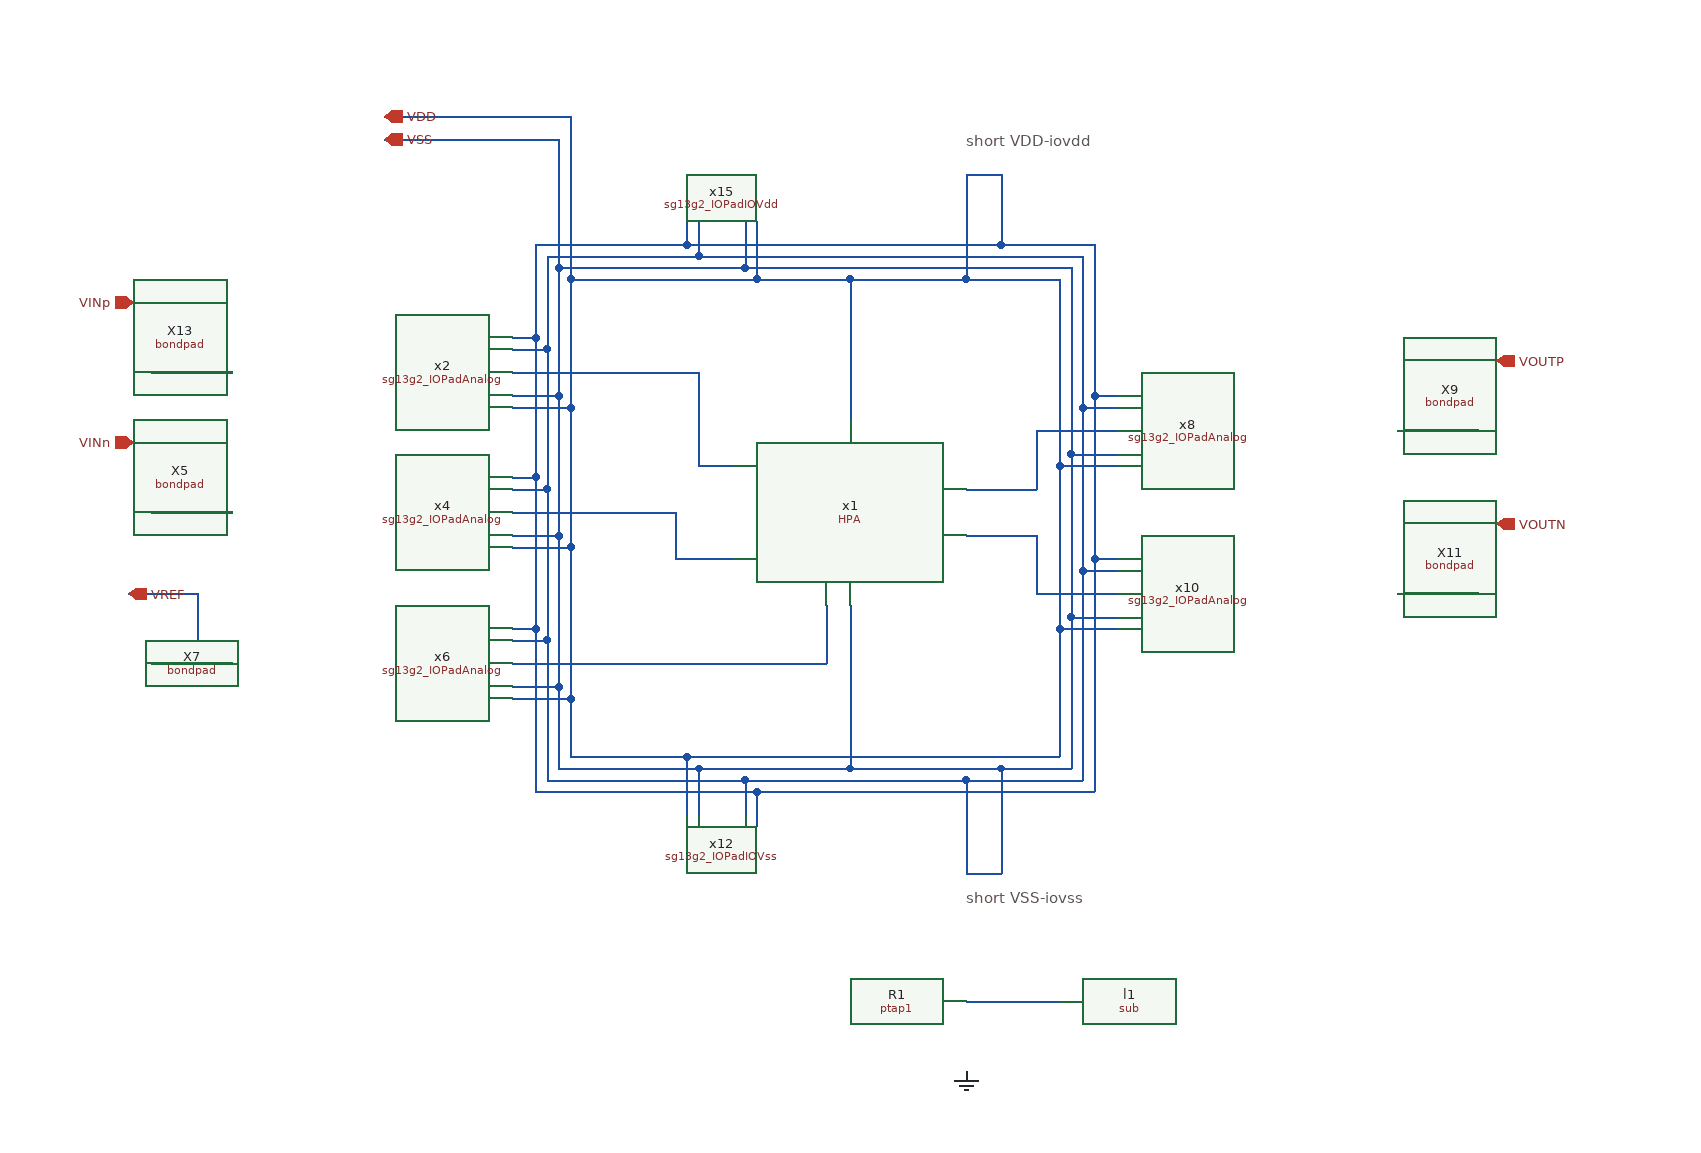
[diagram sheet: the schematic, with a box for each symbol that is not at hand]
v {xschem version=3.4.4 file_version=1.2
}
G {}
K {}
V {}
S {}
E {}
T {short VDD-iovdd} 100 -330 0 0 0.4 0.4 {}
T {short VSS-iovss} 100 320 0 0 0.4 0.4 {}
N -560 0 -530 0 {
lab=VINn}
N -620 -60 -560 -60 {
lab=VINn}
N -560 -60 -560 0 {
lab=VINn}
N -600 0 -560 0 {
lab=VINn}
N -560 130 -530 130 {
lab=VREF}
N -620 70 -560 70 {
lab=VREF}
N -560 70 -560 130 {
lab=VREF}
N -600 130 -560 130 {
lab=VREF}
N -560 -120 -530 -120 {
lab=VINp}
N -620 -180 -560 -180 {
lab=VINp}
N -560 -180 -560 -120 {
lab=VINp}
N -600 -120 -560 -120 {
lab=VINp}
N 470 -70 500 -70 {
lab=VOUTP}
N 500 -130 560 -130 {
lab=VOUTP}
N 500 -130 500 -70 {
lab=VOUTP}
N 500 -70 540 -70 {
lab=VOUTP}
N 470 70 500 70 {
lab=VOUTN}
N 500 10 560 10 {
lab=VOUTN}
N 500 10 500 70 {
lab=VOUTN}
N 500 70 540 70 {
lab=VOUTN}
N -80 -250 -80 -200 {
lab=VDD}
N -240 160 -240 210 {
lab=VDD}
N -90 -250 -90 -210 {
lab=VSS}
N -250 150 -250 220 {
lab=VSS}
N -250 220 -130 220 {
lab=VSS}
N -130 220 -130 260 {
lab=VSS}
N -140 210 -140 260 {
lab=VDD}
N -240 210 -140 210 {
lab=VDD}
N 130 220 190 220 {
lab=VSS}
N -130 -250 -130 -220 {
lab=VSS}
N -260 110 -260 230 {
lab=VSS}
N 100 230 200 230 {
lab=VSS}
N -140 -250 -140 -230 {
lab=VDD}
N -270 -230 -140 -230 {
lab=VDD}
N -80 240 210 240 {
lab=VDD}
N -270 100 -270 240 {
lab=VDD}
N -290 -150 -270 -150 {
lab=VDD}
N -270 -230 -270 -150 {
lab=VDD}
N -290 -140 -260 -140 {
lab=VSS}
N -260 -220 -260 -140 {
lab=VSS}
N -290 -30 -270 -30 {
lab=VDD}
N -270 -150 -270 -30 {
lab=VDD}
N -290 -20 -260 -20 {
lab=VSS}
N -260 -140 -260 -20 {
lab=VSS}
N -290 100 -270 100 {
lab=VDD}
N -270 -30 -270 100 {
lab=VDD}
N -290 110 -260 110 {
lab=VSS}
N -260 -20 -260 110 {
lab=VSS}
N -290 160 -240 160 {
lab=VDD}
N -240 30 -240 160 {
lab=VDD}
N -290 150 -250 150 {
lab=VSS}
N -250 20 -250 150 {
lab=VSS}
N -290 -90 -240 -90 {
lab=VDD}
N -290 -100 -250 -100 {
lab=VSS}
N -250 -210 -250 -100 {
lab=VSS}
N 180 100 180 210 {
lab=VDD}
N 100 -200 180 -200 {
lab=VDD}
N 190 90 190 220 {
lab=VSS}
N -90 -210 190 -210 {
lab=VSS}
N 200 50 200 230 {
lab=VSS}
N -130 -220 200 -220 {
lab=VSS}
N -260 -220 -130 -220 {
lab=VSS}
N 210 40 210 240 {
lab=VDD}
N 130 -230 210 -230 {
lab=VDD}
N 210 -100 230 -100 {
lab=VDD}
N 210 -230 210 -100 {
lab=VDD}
N 200 -90 230 -90 {
lab=VSS}
N 200 -220 200 -90 {
lab=VSS}
N 190 -50 230 -50 {
lab=VSS}
N 190 -210 190 -50 {
lab=VSS}
N 180 -40 230 -40 {
lab=VDD}
N 180 -200 180 -40 {
lab=VDD}
N 210 40 230 40 {
lab=VDD}
N 210 -100 210 40 {
lab=VDD}
N 200 50 230 50 {
lab=VSS}
N 200 -90 200 50 {
lab=VSS}
N 190 90 230 90 {
lab=VSS}
N 190 -50 190 90 {
lab=VSS}
N 180 100 230 100 {
lab=VDD}
N 180 -40 180 100 {
lab=VDD}
N -140 210 180 210 {
lab=VDD}
N -130 220 0 220 {
lab=VSS}
N -240 -200 -80 -200 {
lab=VDD}
N -250 -210 -90 -210 {
lab=VSS}
N -250 -320 -250 -210 {
lab=VSS}
N -240 -200 -240 -90 {
lab=VDD}
N -400 -320 -250 -320 {
lab=VSS}
N -240 -340 -240 -200 {
lab=VDD}
N -400 -340 -240 -340 {
lab=VDD}
N 0 -200 0 -80 {
lab=VDD}
N -80 -200 0 -200 {
lab=VDD}
N 0 80 0 220 {
lab=VSS}
N 100 -20 160 -20 {
lab=#net1}
N 160 -70 160 -20 {
lab=#net1}
N 160 -70 230 -70 {
lab=#net1}
N 100 20 160 20 {
lab=#net2}
N 160 20 160 70 {
lab=#net2}
N 160 70 230 70 {
lab=#net2}
N 100 -290 100 -200 {
lab=VDD}
N 0 -200 100 -200 {
lab=VDD}
N 100 -290 130 -290 {
lab=VDD}
N 130 -290 130 -230 {
lab=VDD}
N -140 -230 130 -230 {
lab=VDD}
N 130 220 130 310 {
lab=VSS}
N 100 310 130 310 {
lab=VSS}
N 0 220 130 220 {
lab=VSS}
N 100 230 100 310 {
lab=VSS}
N -90 230 100 230 {
lab=VSS}
N -20 80 -20 130 {
lab=#net3}
N -290 130 -20 130 {
lab=#net3}
N -290 -120 -130 -120 {
lab=#net4}
N -130 -120 -130 -40 {
lab=#net4}
N -130 -40 -100 -40 {
lab=#net4}
N -290 0 -150 -0 {
lab=#net5}
N -150 40 -100 40 {
lab=#net5}
N -150 -0 -150 40 {
lab=#net5}
N -290 20 -250 20 {
lab=VSS}
N -250 -100 -250 20 {
lab=VSS}
N -290 30 -240 30 {
lab=VDD}
N -240 -90 -240 30 {
lab=VDD}
N -80 240 -80 270 {
lab=VDD}
N -270 240 -80 240 {
lab=VDD}
N -90 230 -90 260 {
lab=VSS}
N -260 230 -90 230 {
lab=VSS}
N 100 420 180 420 {}
C {HPA.sym} -20 0 0 0 {name=x1}
C {sg13g2_IOPadIOVdd.sym} -110 -370 3 0 {name=x15}
C {sg13g2_IOPadIOVss.sym} -110 380 1 0 {name=x12}
C {sg13g2_pr/bondpad.sym} -640 0 3 0 {name=X5
model=bondpad
spiceprefix=X
size=80u
shape=0
padtype=0
}
C {sg13g2_pr/bondpad.sym} -640 130 3 0 {name=X7
model=bondpad
spiceprefix=X
size=80u
shape=0
padtype=0
}
C {sg13g2_pr/bondpad.sym} -640 -120 3 0 {name=X13
model=bondpad
spiceprefix=X
size=80u
shape=0
padtype=0
}
C {IOCells/sg13g2_IOPadAnalog.sym} -410 -120 0 1 {name=x2}
C {IOCells/sg13g2_IOPadAnalog.sym} -410 0 0 1 {name=x4}
C {IOCells/sg13g2_IOPadAnalog.sym} -410 130 0 1 {name=x6}
C {sg13g2_pr/bondpad.sym} 580 -70 1 1 {name=X9
model=bondpad
spiceprefix=X
size=80u
shape=0
padtype=0
}
C {sg13g2_pr/bondpad.sym} 580 70 1 1 {name=X11
model=bondpad
spiceprefix=X
size=80u
shape=0
padtype=0
}
C {opin.sym} 555 -130 0 0 {name=p8 lab=VOUTP}
C {opin.sym} 555 10 0 0 {name=p22 lab=VOUTN}
C {IOCells/sg13g2_IOPadAnalog.sym} 350 -70 0 0 {name=x8}
C {IOCells/sg13g2_IOPadAnalog.sym} 350 70 0 0 {name=x10}
C {iopin.sym} -620 70 0 1 {name=p35 lab=VREF}
C {ipin.sym} -615 -60 0 0 {name=p21 lab=VINn}
C {ipin.sym} -615 -180 0 0 {name=p26 lab=VINp}
C {iopin.sym} -400 -340 0 1 {name=p1 lab=VDD}
C {iopin.sym} -400 -320 0 1 {name=p2 lab=VSS}
C {sg13g2_pr/ptap1.sym} 100 450 0 0 {name=R1
model=ptap1
spiceprefix=X
w=0.78e-6
l=0.78e-6
}
C {sg13g2_pr/sub.sym} 180 420 0 0 {name=l1 lab=sub!}
C {gnd.sym} 100 480 0 0 {name=l2 lab=GND}
